VERSION 5.8 ;
BUSBITCHARS "[]" ;
DIVIDERCHAR "/" ;
UNITS
  DATABASE MICRONS 1000 ;
END UNITS
MANUFACTURINGGRID 0.001 ;
SITE TR1um_site
  CLASS CORE ;
  SIZE 0.100 BY 62.600 ;
  SYMMETRY X Y ;
END TR1um_site
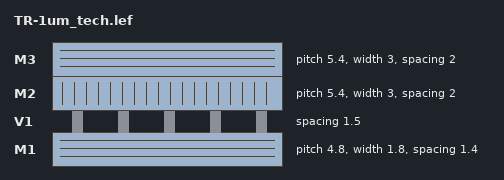
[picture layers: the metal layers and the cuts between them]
LAYER M1
  TYPE ROUTING ;
  DIRECTION HORIZONTAL ;
  WIDTH 1.8 ;
  MINWIDTH 1.8 ;
  SPACING 1.4 ;
  PITCH 4.8 ;
  AREA 3.24 ;
  RESISTANCE RPERSQ 0.050 ;
  # Derived nominal sheet resistance estimate; no foundry RC/PEX data supplied.
  CAPACITANCE CPERSQDIST 0.000035 ;
  EDGECAPACITANCE 0.000050 ;
END M1
LAYER V1
  TYPE CUT ;
  SPACING 1.5 ;
  RESISTANCE 1.000 ;
  # Engineering nominal via resistance; sensitivity range is 0.5..2.0 ohm.
END V1
LAYER M2
  TYPE ROUTING ;
  DIRECTION VERTICAL ;
  WIDTH 3.0 ;
  MINWIDTH 3.0 ;
  SPACING 2.0 ;
  PITCH 5.4 ;
  AREA 9.0 ;
  RESISTANCE RPERSQ 0.030 ;
  # Derived nominal sheet resistance estimate; no foundry RC/PEX data supplied.
  CAPACITANCE CPERSQDIST 0.0000175 ;
  EDGECAPACITANCE 0.000050 ;
END M2
VIA M1M2_V1 DEFAULT
  LAYER M1 ;
    RECT -1.7 -1.7 1.7 1.7 ;
  LAYER V1 ;
    RECT -0.7 -0.7 0.7 0.7 ;
  LAYER M2 ;
    RECT -1.7 -1.7 1.7 1.7 ;
END M1M2_V1
LAYER M3
  TYPE ROUTING ;
  DIRECTION HORIZONTAL ;
  WIDTH 3.0 ;
  MINWIDTH 3.0 ;
  SPACING 2.0 ;
  PITCH 5.4 ;
  AREA 9.0 ;
  RESISTANCE RPERSQ 0.030 ;
  # Derived nominal sheet resistance estimate; no foundry RC/PEX data supplied.
  CAPACITANCE CPERSQDIST 0.000020 ;
  EDGECAPACITANCE 0.000050 ;
END M3
END LIBRARY
